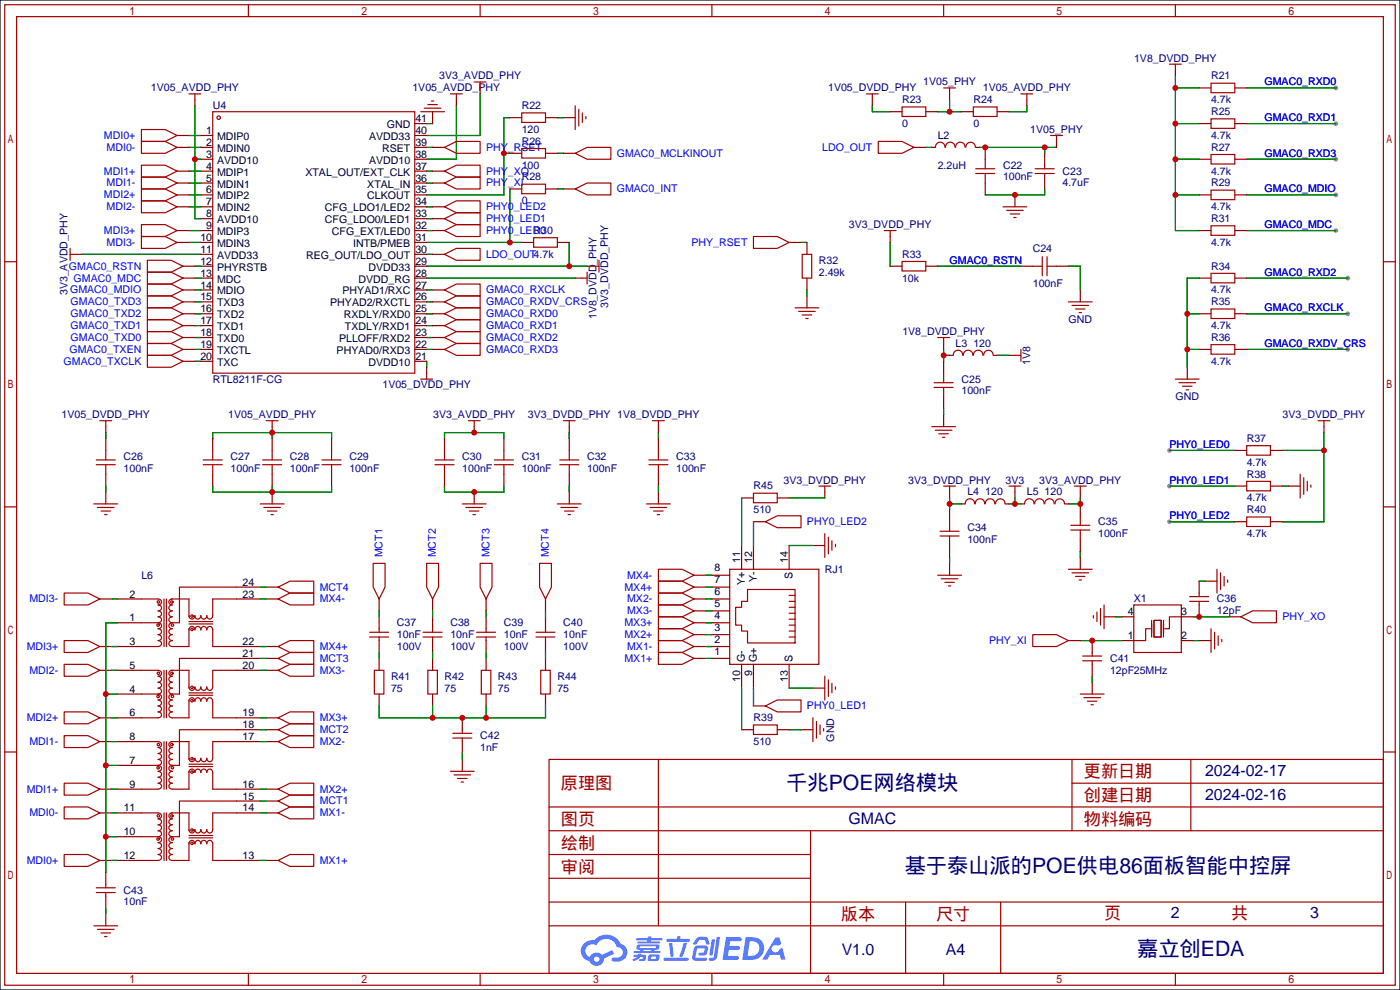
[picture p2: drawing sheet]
<svg xmlns="http://www.w3.org/2000/svg" width="299mm" height="212mm" viewBox="0 0 299 212" stroke-linecap="round" stroke-linejoin="round" font-family="sans-serif">
<defs><g id="words">
<g font-size="4.5" fill="#000080">
<text x="168" y="168.8">千兆POE网络模块</text>
<text x="193.4" y="186.6">基于泰山派的POE供电86面板智能中控屏</text>
<text x="243" y="204.4">嘉立创EDA</text>
</g>
<g font-size="3.7" fill="#a00000">
<text x="231.6" y="166.2">更新日期</text>
<text x="119.9" y="168.7">原理图</text>
<text x="231.6" y="171.2">创建日期</text>
<text x="119.9" y="176.3">图页</text>
<text x="231.6" y="176.3">物料编码</text>
<text x="119.9" y="181.4">绘制</text>
<text x="119.9" y="186.5">审阅</text>
<text x="179.7" y="196.6">版本</text>
<text x="200" y="196.6">尺寸</text>
<text x="236" y="196.4">页</text>
<text x="263.1" y="196.4">共</text>
</g>
<g font-size="3.4" fill="#000080">
<text x="257.6" y="165.9">2024-02-17</text>
<text x="257.6" y="171">2024-02-16</text>
<text x="181.3" y="176.1">GMAC</text>
<text x="250.3" y="196.2">2</text>
<text x="280" y="196.2">3</text>
<text x="179.9" y="204">V1.0</text>
<text x="202.1" y="204">A4</text>
</g>
<g font-size="2.3" fill="#000080">
<text x="93.9" y="17">3V3_AVDD_PHY</text>
<text x="242.4" y="13.2">1V8_DVDD_PHY</text>
<text x="258.8" y="17">R21</text>
<text x="32.3" y="19.5">1V05_AVDD_PHY</text>
<text x="45.5" y="23.3">U4</text>
<text x="88.1" y="19.5">1V05_AVDD_PHY</text>
<text x="111.5" y="23.3">R22</text>
<text x="177" y="19.5">1V05_DVDD_PHY</text>
<text x="192.8" y="22.1">R23</text>
<text x="197.3" y="18.3">1V05_PHY</text>
<text x="208" y="22.1">R24</text>
<text x="210.1" y="19.5">1V05_AVDD_PHY</text>
<text x="258.8" y="22.1">4.7k</text>
<text x="111.5" y="28.4">120</text>
<text x="192.8" y="27.1">0</text>
<text x="200.4" y="29.7">L2</text>
<text x="208" y="27.1">0</text>
<text x="220.2" y="28.4">1V05_PHY</text>
<text x="258.8" y="24.6">R25</text>
<text x="258.8" y="29.7">4.7k</text>
<text x="111.5" y="31">R26</text>
<text x="258.8" y="32.2">R27</text>
<text x="111.5" y="38.6">R28</text>
<text x="111.5" y="36">100</text>
<text x="200.4" y="36">2.2uH</text>
<text x="214.4" y="36">C22</text>
<text x="214.4" y="38.6">100nF</text>
<text x="227.1" y="37.3">C23</text>
<text x="227.1" y="39.8">4.7uF</text>
<text x="258.8" y="37.3">4.7k</text>
<text x="258.8" y="39.8">R29</text>
<text x="111.5" y="43.7">0</text>
<text x="258.8" y="44.9">4.7k</text>
<text x="258.8" y="47.5">R31</text>
<text x="114" y="50">R30</text>
<text x="181.4" y="48.7">3V3_DVDD_PHY</text>
<text x="220.7" y="53.8">C24</text>
<text x="258.8" y="52.5">4.7k</text>
<text x="175" y="56.4">R32</text>
<text x="175" y="58.9">2.49k</text>
<text x="192.8" y="55.1">R33</text>
<text x="258.8" y="57.6">R34</text>
<text x="14.4" y="63.1" transform="rotate(-90 14.4 63.1)">3V3_AVDD_PHY</text>
<text x="130" y="65.7" transform="rotate(-90 130 65.7)">3V3_DVDD_PHY</text>
<text x="192.8" y="60.2">10k</text>
<text x="220.7" y="61.4">100nF</text>
<text x="258.8" y="62.7">4.7k</text>
<text x="258.8" y="65.2">R35</text>
<text x="127.5" y="68.3" transform="rotate(-90 127.5 68.3)">1V8_DVDD_PHY</text>
<text x="192.9" y="71.6">1V8_DVDD_PHY</text>
<text x="228.4" y="69.1">GND</text>
<text x="258.8" y="70.3">4.7k</text>
<text x="204.2" y="74.1">L3</text>
<text x="208" y="74.1">120</text>
<text x="220.2" y="78" transform="rotate(-90 220.2 78)">1V8</text>
<text x="258.8" y="72.9">R36</text>
<text x="258.8" y="77.9">4.7k</text>
<text x="45.5" y="81.8">RTL8211F-CG</text>
<text x="81.7" y="83">1V05_DVDD_PHY</text>
<text x="205.5" y="81.8">C25</text>
<text x="13.2" y="89.4">1V05_DVDD_PHY</text>
<text x="48.8" y="89.4">1V05_AVDD_PHY</text>
<text x="92.6" y="89.4">3V3_AVDD_PHY</text>
<text x="112.8" y="89.4">3V3_DVDD_PHY 1V8_DVDD_PHY</text>
<text x="205.5" y="84.3">100nF</text>
<text x="251.2" y="85.6">GND</text>
<text x="274.1" y="89.4">3V3_DVDD_PHY</text>
<text x="266.4" y="94.5">R37</text>
<text x="26.4" y="98.3">C26</text>
<text x="26.4" y="100.8">100nF</text>
<text x="49.3" y="98.3">C27</text>
<text x="49.3" y="100.8">100nF</text>
<text x="62" y="98.3">C28</text>
<text x="62" y="100.8">100nF</text>
<text x="74.7" y="98.3">C29</text>
<text x="74.7" y="100.8">100nF</text>
<text x="98.8" y="98.3">C30</text>
<text x="98.8" y="100.8">100nF</text>
<text x="111.5" y="98.3">C31</text>
<text x="111.5" y="100.8">100nF</text>
<text x="125.5" y="98.3">C32</text>
<text x="125.5" y="100.8">100nF</text>
<text x="144.5" y="98.3">C33</text>
<text x="144.5" y="100.8">100nF</text>
<text x="266.4" y="99.5">4.7k</text>
<text x="161" y="104.6">R45</text>
<text x="167.5" y="103.3">3V3_DVDD_PHY</text>
<text x="194.1" y="103.3">3V3_DVDD_PHY</text>
<text x="206.8" y="105.9">L4</text>
<text x="210.6" y="105.9">120</text>
<text x="214.9" y="103.3">3V3</text>
<text x="219.5" y="105.9">L5</text>
<text x="222.1" y="103.3">3V3_AVDD_PHY</text>
<text x="223.3" y="105.9">120</text>
<text x="266.4" y="102.1">R38</text>
<text x="266.4" y="107.2">4.7k</text>
<text x="161" y="109.7">510</text>
<text x="206.8" y="113.5">C34</text>
<text x="234.7" y="112.2">C35</text>
<text x="266.4" y="109.7">R40</text>
<text x="206.8" y="116">100nF</text>
<text x="234.7" y="114.8">100nF</text>
<text x="266.4" y="114.8">4.7k</text>
<text x="30.2" y="123.7">L6</text>
<text x="176.3" y="122.4">RJ1</text>
<text x="242.3" y="128.7">X1</text>
<text x="260.1" y="128.7">C36</text>
<text x="260.1" y="131.3">12pF</text>
<text x="84.8" y="133.8">C37</text>
<text x="84.8" y="136.4">10nF</text>
<text x="96.3" y="133.8">C38</text>
<text x="96.3" y="136.4">10nF</text>
<text x="107.7" y="133.8">C39</text>
<text x="107.7" y="136.4">10nF</text>
<text x="120.4" y="133.8">C40</text>
<text x="120.4" y="136.4">10nF</text>
<text x="84.8" y="138.9">100V</text>
<text x="96.3" y="138.9">100V</text>
<text x="107.7" y="138.9">100V</text>
<text x="120.4" y="138.9">100V</text>
<text x="237.2" y="141.4">C41</text>
<text x="237.2" y="144">12pF25MHz</text>
<text x="83.6" y="145.3">R41</text>
<text x="83.6" y="147.8">75</text>
<text x="95" y="145.3">R42</text>
<text x="95" y="147.8">75</text>
<text x="106.4" y="145.3">R43</text>
<text x="106.4" y="147.8">75</text>
<text x="119.1" y="145.3">R44</text>
<text x="119.1" y="147.8">75</text>
<text x="161" y="154.1">R39</text>
<text x="102.6" y="158">C42</text>
<text x="102.6" y="160.5">1nF</text>
<text x="161" y="159.2">510</text>
<text x="178.3" y="158.5" transform="rotate(-90 178.3 158.5)">GND</text>
<text x="26.4" y="191">C43</text>
<text x="26.4" y="193.5">10nF</text>
</g>
<g font-size="2.3" fill="#00f">
<text x="270.3" y="18.3">GMAC0_RXD0</text>
<text x="22.2" y="29.7">MDI0+</text>
<text x="270.3" y="25.9">GMAC0_RXD1</text>
<text x="22.8" y="32.2">MDI0-</text>
<text x="103.9" y="32.2">PHY_RSET</text>
<text x="131.8" y="33.5">GMAC0_MCLKINOUT</text>
<text x="175.7" y="32.2">LDO_OUT</text>
<text x="270.3" y="33.5">GMAC0_RXD3</text>
<text x="22.2" y="37.3">MDI1+</text>
<text x="22.8" y="39.8">MDI1-</text>
<text x="103.9" y="39.8">PHY_XI</text>
<text x="103.9" y="37.3">PHY_XO</text>
<text x="131.8" y="41.1">GMAC0_INT</text>
<text x="270.3" y="41.1">GMAC0_MDIO</text>
<text x="22.2" y="42.4">MDI2+</text>
<text x="22.8" y="44.9">MDI2-</text>
<text x="103.9" y="47.5">PHY0_LED1</text>
<text x="103.9" y="44.9">PHY0_LED2</text>
<text x="22.2" y="50">MDI3+</text>
<text x="22.8" y="52.5">MDI3-</text>
<text x="103.9" y="50">PHY0_LED0</text>
<text x="147.8" y="52.5">PHY_RSET</text>
<text x="270.3" y="48.7">GMAC0_MDC</text>
<text x="14.7" y="57.6">GMAC0_RSTN</text>
<text x="103.9" y="55.1">LDO_OUT4.7k</text>
<text x="202.9" y="56.4">GMAC0_RSTN</text>
<text x="270.3" y="58.9">GMAC0_RXD2</text>
<text x="15" y="62.7">GMAC0_MDIO</text>
<text x="15.1" y="65.2">GMAC0_TXD3</text>
<text x="15.7" y="60.2">GMAC0_MDC</text>
<text x="103.9" y="65.2">GMAC0_RXDV_CRS</text>
<text x="103.9" y="62.7">GMAC0_RXCLK</text>
<text x="15.1" y="70.3">GMAC0_TXD1</text>
<text x="15.1" y="67.8">GMAC0_TXD2</text>
<text x="103.9" y="67.8">GMAC0_RXD0</text>
<text x="103.9" y="70.3">GMAC0_RXD1</text>
<text x="270.3" y="66.5">GMAC0_RXCLK</text>
<text x="13.6" y="77.9">GMAC0_TXCLK</text>
<text x="14.9" y="75.4">GMAC0_TXEN</text>
<text x="15.1" y="72.9">GMAC0_TXD0</text>
<text x="103.9" y="72.9">GMAC0_RXD2</text>
<text x="103.9" y="75.4">GMAC0_RXD3</text>
<text x="270.3" y="74.1">GMAC0_RXDV_CRS</text>
<text x="249.9" y="95.7">PHY0_LED0</text>
<text x="249.9" y="103.3">PHY0_LED1</text>
<text x="172.5" y="112.2">PHY0_LED2</text>
<text x="249.9" y="111">PHY0_LED2</text>
<text x="81.8" y="119.1" transform="rotate(-90 81.8 119.1)">MCT1</text>
<text x="93.2" y="119.1" transform="rotate(-90 93.2 119.1)">MCT2</text>
<text x="104.6" y="119.1" transform="rotate(-90 104.6 119.1)">MCT3</text>
<text x="117.3" y="119.1" transform="rotate(-90 117.3 119.1)">MCT4</text>
<text x="134" y="123.7">MX4-</text>
<text x="6.3" y="128.7">MDI3-</text>
<text x="68.3" y="126.2">MCT4</text>
<text x="68.3" y="128.7">MX4-</text>
<text x="133.5" y="126.2">MX4+</text>
<text x="134" y="128.7">MX2-</text>
<text x="134" y="131.3">MX3-</text>
<text x="133.5" y="136.4">MX2+</text>
<text x="133.5" y="133.8">MX3+</text>
<text x="211.4" y="137.6">PHY_XI</text>
<text x="274.1" y="132.6">PHY_XO</text>
<text x="5.7" y="138.9">MDI3+</text>
<text x="6.3" y="144">MDI2-</text>
<text x="68.3" y="141.4">MCT3</text>
<text x="68.3" y="138.9">MX4+</text>
<text x="68.3" y="144">MX3-</text>
<text x="133.5" y="141.4">MX1+</text>
<text x="134" y="138.9">MX1-</text>
<text x="5.7" y="154.1">MDI2+</text>
<text x="68.3" y="154.1">MX3+</text>
<text x="172.5" y="151.6">PHY0_LED1</text>
<text x="6.3" y="159.2">MDI1-</text>
<text x="68.3" y="156.7">MCT2</text>
<text x="68.3" y="159.2">MX2-</text>
<text x="5.7" y="169.4">MDI1+</text>
<text x="68.3" y="171.9">MCT1</text>
<text x="68.3" y="169.4">MX2+</text>
<text x="6.3" y="174.5">MDI0-</text>
<text x="68.3" y="174.5">MX1-</text>
<text x="5.7" y="184.6">MDI0+</text>
<text x="68.3" y="184.6">MX1+</text>
</g>
<g font-size="2.3">
<text x="44.1" y="28.6">1</text>
<text x="46.4" y="29.9">MDIP0</text>
<text x="78.9" y="29.9">AVDD33</text>
<text x="82.7" y="27.4">GND</text>
<text x="88.8" y="28.6">40</text>
<text x="88.8" y="26.1">41</text>
<text x="44.1" y="31.2">2</text>
<text x="44.1" y="33.7">3</text>
<text x="46.4" y="32.5">MDIN0</text>
<text x="46.4" y="35">AVDD10</text>
<text x="78.9" y="35">AVDD10</text>
<text x="81.7" y="32.5">RSET</text>
<text x="88.8" y="33.7">38</text>
<text x="88.8" y="31.2">39</text>
<text x="44.1" y="36.3">4</text>
<text x="44.1" y="38.8">5</text>
<text x="44.1" y="41.3">6</text>
<text x="46.4" y="37.5">MDIP1</text>
<text x="46.4" y="40.1">MDIN1</text>
<text x="65.3" y="37.5">XTAL_OUT/EXT_CLK</text>
<text x="78.5" y="40.1">XTAL_IN</text>
<text x="88.8" y="41.3">35</text>
<text x="88.8" y="38.8">36</text>
<text x="88.8" y="36.3">37</text>
<text x="44.1" y="43.9">7</text>
<text x="44.1" y="46.4">8</text>
<text x="46.4" y="42.6">MDIP2</text>
<text x="46.4" y="45.2">MDIN2</text>
<text x="46.4" y="47.7">AVDD10</text>
<text x="69.4" y="47.7">CFG_LDO0/LED1</text>
<text x="69.4" y="45.2">CFG_LDO1/LED2</text>
<text x="78.5" y="42.6">CLKOUT</text>
<text x="88.8" y="46.4">33</text>
<text x="88.8" y="43.9">34</text>
<text x="42.8" y="51.5">10</text>
<text x="44.1" y="49">9</text>
<text x="46.4" y="50.2">MDIP3</text>
<text x="46.4" y="52.8">MDIN3</text>
<text x="70.9" y="50.2">CFG_EXT/LED0</text>
<text x="75.5" y="52.8">INTB/PMEB</text>
<text x="88.8" y="51.5">31</text>
<text x="88.8" y="49">32</text>
<text x="42.8" y="54">11</text>
<text x="42.8" y="56.6">12</text>
<text x="42.8" y="59.1">13</text>
<text x="46.4" y="55.3">AVDD33</text>
<text x="46.4" y="57.9">PHYRSTB</text>
<text x="65.4" y="55.3">REG_OUT/LDO_OUT</text>
<text x="78.8" y="57.9">DVDD33</text>
<text x="88.8" y="59.1">28</text>
<text x="88.8" y="56.6">29</text>
<text x="88.8" y="54">30</text>
<text x="42.8" y="61.7">14</text>
<text x="42.8" y="64.2">15</text>
<text x="46.4" y="60.4">MDC</text>
<text x="46.4" y="62.9">MDIO</text>
<text x="46.4" y="65.5">TXD3</text>
<text x="70.6" y="65.5">PHYAD2/RXCTL</text>
<text x="73.2" y="62.9">PHYAD1/RXC</text>
<text x="76.6" y="60.4">DVDD_RG</text>
<text x="88.8" y="64.2">26</text>
<text x="88.8" y="61.7">27</text>
<text x="42.8" y="66.7">16</text>
<text x="42.8" y="69.3">17</text>
<text x="42.8" y="71.8">18</text>
<text x="46.4" y="68">TXD2</text>
<text x="46.4" y="70.6">TXD1</text>
<text x="73.5" y="68">RXDLY/RXD0</text>
<text x="73.7" y="70.6">TXDLY/RXD1</text>
<text x="88.8" y="71.8">23</text>
<text x="88.8" y="69.3">24</text>
<text x="88.8" y="66.7">25</text>
<text x="42.8" y="74.4">19</text>
<text x="42.8" y="76.9">20</text>
<text x="46.4" y="73.1">TXD0</text>
<text x="46.4" y="75.6">TXCTL</text>
<text x="72" y="75.6">PHYAD0/RXD3</text>
<text x="72.5" y="73.1">PLLOFF/RXD2</text>
<text x="88.8" y="76.9">21</text>
<text x="88.8" y="74.4">22</text>
<text x="46.4" y="78.2">TXC</text>
<text x="78.8" y="78.2">DVDD10</text>
<text x="51.8" y="125.2">24</text>
<text x="152.7" y="124.7">7</text>
<text x="152.7" y="122.1">8</text>
<text x="158.2" y="120.4" transform="rotate(-90 158.2 120.4)">11</text>
<text x="159.2" y="125" transform="rotate(-90 159.2 125)">Y+</text>
<text x="160.7" y="120.4" transform="rotate(-90 160.7 120.4)">12</text>
<text x="161.7" y="124.4" transform="rotate(-90 161.7 124.4)">Y-</text>
<text x="168.3" y="120.4" transform="rotate(-90 168.3 120.4)">14</text>
<text x="169.4" y="123.7" transform="rotate(-90 169.4 123.7)">S</text>
<text x="27.7" y="127.7">2</text>
<text x="51.8" y="127.7">23</text>
<text x="152.7" y="129.8">5</text>
<text x="152.7" y="127.2">6</text>
<text x="241.1" y="131.5">4</text>
<text x="252.5" y="131.5">3</text>
<text x="27.7" y="137.9">3</text>
<text x="27.7" y="132.8">1</text>
<text x="51.8" y="137.9">22</text>
<text x="152.7" y="137.4">2</text>
<text x="152.7" y="134.8">3</text>
<text x="152.7" y="132.3">4</text>
<text x="241.1" y="136.6">1</text>
<text x="252.5" y="136.6">2</text>
<text x="27.7" y="142.9">5</text>
<text x="51.8" y="140.4">21</text>
<text x="51.8" y="142.9">20</text>
<text x="152.7" y="139.9">1</text>
<text x="159.2" y="141.5" transform="rotate(-90 159.2 141.5)">G-</text>
<text x="161.7" y="141.5" transform="rotate(-90 161.7 141.5)">G+</text>
<text x="169.4" y="141.5" transform="rotate(-90 169.4 141.5)">S</text>
<text x="27.7" y="148">4</text>
<text x="158.2" y="145.8" transform="rotate(-90 158.2 145.8)">10</text>
<text x="160.7" y="144.5" transform="rotate(-90 160.7 144.5)">9</text>
<text x="168.3" y="145.8" transform="rotate(-90 168.3 145.8)">13</text>
<text x="27.7" y="153.1">6</text>
<text x="51.8" y="153.1">19</text>
<text x="51.8" y="155.6">18</text>
<text x="27.7" y="158.2">8</text>
<text x="51.8" y="158.2">17</text>
<text x="27.7" y="163.3">7</text>
<text x="26.4" y="173.4">11</text>
<text x="27.7" y="168.3">9</text>
<text x="51.8" y="168.3">16</text>
<text x="51.8" y="170.9">15</text>
<text x="51.8" y="173.4">14</text>
<text x="26.4" y="178.5">10</text>
<text x="26.4" y="183.6">12</text>
<text x="51.8" y="183.6">13</text>
</g>
</g></defs>
<path d="M0 0h299.2v211.6h-299.2z" fill="#fff" stroke="#000" stroke-width=".25"/>
<g fill="#999">
<circle cx="285.5" cy="18.8" r=".51"/>
<circle cx="285.5" cy="26.4" r=".51"/>
<circle cx="285.5" cy="34" r=".51"/>
<circle cx="288" cy="59.4" r=".51"/>
<circle cx="288" cy="67.1" r=".51"/>
<circle cx="288" cy="74.7" r=".51"/>
<circle cx="285.5" cy="41.7" r=".51"/>
<circle cx="285.5" cy="49.3" r=".51"/>
<circle cx="249.9" cy="96.3" r=".51"/>
<circle cx="249.9" cy="103.9" r=".51"/>
<circle cx="249.9" cy="111.5" r=".51"/>
</g>
<g fill="none" stroke="#a10000" stroke-width=".25">
<path d="M1 1h297.2v209.6h-297.2zM3.6 3.6h292.1v204.4h-292.1zM53.1 1v2.6M102.6 1v2.6M152.1 1v2.6M201.7 1v2.6M251.2 1v2.6M1 55.9h2.6M295.7 55.9h2.5M1 108.3h2.6M295.7 108.3h2.5M1 160.7h2.6"/>
<path d="M117.3 162.3h178.4v45.7h-178.4zM117.3 177.5h178.4M117.3 172.5h178.4M140.7 162.3v35.6M173.2 177.5v30.5M229.1 162.3v15.2M229.1 167.4h66.6M254.5 162.3v15.2M295.7 160.7h2.5M117.3 182.6h55.9M117.3 197.9h178.4M117.3 192.8h178.4"/>
<path d="M117.3 187.7h55.9M193.5 192.8v15.2M213.9 192.8v15.2M53.1 208v2.6M102.6 208v2.6M152.1 208v2.6M201.7 208v2.6M251.2 208v2.6"/>
</g>
<g fill="#5487ff">
<path d="M155.2 200.3h2.6a.48 .48 0 0 1 .7 .4 .48 .48 0 0 1-.6 .4h-1.8l-.2 1.1h1.9a.43 .43 0 0 1 .4 .4 .43 .43 0 0 1-.5 .4h-1.9l-.2 1.3h1.7a.45 .45 0 0 1 .5 .2 .45 .45 0 0 1-.1 .6h-3.3z"/>
<path d="M165.7 200.3h.9l.4 1.5-.8 .3a.84 .84 0 0 0-1.2 .3 .84 .84 0 0 0 .4 1.1 .84 .84 0 0 0 1.1-.4l.1-.2 .6-.3 .7 2.5h-1l-.2-1h-2.1l-.6 1h-1.1z"/>
<path d="M152.1 200.8h.7l-.5 3.1a.36 .36 0 0 1-.3 .3 .36 .36 0 0 1-.4-.3z"/>
<path d="M153.2 200.2h.7l-.6 4.3a1.13 1.13 0 0 1-1.8 .6l.2-.4h.7l.2-.2z"/>
<path d="M148.9 200.6l.6-.4h1a.77 .77 0 0 1 .9 .5l.3 1-.2 .2h-.5l-.3-.9-.2-.2-1 .1-.7 1-.6-.1-.1-.2z"/>
<path d="M148.4 202.4l.6-.3h1.7a.81 .81 0 0 1 .7 .5 .81 .81 0 0 1-.2 .8 .81 .81 0 0 1-.9 .8h-.7a.32 .32 0 0 1-.3-.3 .32 .32 0 0 1 .4-.3h.7l.2-.9-1.6 .1-.4 1.8 2.2 .1a.32 .32 0 0 1 .3 .4 .32 .32 0 0 1-.4 .2h-2.2l-.5-.3-.1-.5z"/>
<path d="M141.9 204.7h5a.33 .33 0 0 1 .3 .3 .33 .33 0 0 1-.3 .3h-4.9l-.2-.1z"/>
<path d="M146.1 201.5h.8l-.7 2a.98 .98 0 0 1-.7 1.1l-.3-.3z"/>
<path d="M143 201.6h.7l.3 2.5a.34 .34 0 0 1-.3 .4 .34 .34 0 0 1-.4-.3z"/>
<path d="M142.5 200.7h2.1l.3-.6h.6l-.1 .6h1.7a.32 .32 0 0 1 .4 .3 .32 .32 0 0 1-.4 .3h-4.5l-.2-.2z"/>
<path d="M135.5 204.1h.9l.1-.3h.6v.3h.8a.82 .82 0 0 1-.5 1.3h-.8v-.4l.7-.1 .1-.3a.68 .68 0 0 0-1 .4l-1.1 .4-.1-.4 .9-.5h-.7z"/>
<path d="M136 200.5h2.4l.1-.3h.7v.3h2.2l.2 .3-.2 .2h-2.3v.2h1.8l.2 .3-.2 .1h-4.5l-.1-.4h2l.1-.2h-2.3l-.1-.2z"/>
<path d="M159.4 200.3l-.8 4.9h1.7a2.5 2.5 0 0 0 3-2.5 2.5 2.5 0 0 0-3.1-2.4zM160.3 201.1a1.61 1.61 0 0 1 2 1.5 1.61 1.61 0 0 1-1.8 1.7h-.7z"/>
<path d="M136.2 202a.55 .55 0 0 0-.2 .8 .55 .55 0 0 0 .7 .2l.1 .3h-1.3v.3l5.4 .1 .3-.2-.2-.2h-1.2l.2-.3a.7 .7 0 0 0 .8-.3 .7 .7 0 0 0 0-.8l-4.2-.1zM136.8 202.3l3.3-.1 .1 .1-.2 .3h-3.2zM137.5 203h1.7l-.2 .3h-1.4z"/>
<path d="M138.6 204.2a1.05 1.05 0 0 0 0 1.2 2.91 2.91 0 0 0 2.2-.2 .98 .98 0 0 0 0-1.2h-1.6zM139.2 204.5l.9-.1 .1 .4-.2 .2-.8-.1z"/>
<path d="M124.9 201.6a2.23 2.23 0 0 0-.7 2.3 2.23 2.23 0 0 0 1.8 1.6 1.58 1.58 0 0 0 1.8 .9 1.58 1.58 0 0 0 1.3-1.5l2.2-1.1-.5-.7-2.1 1a1.65 1.65 0 0 0-2.7 .4 1.45 1.45 0 0 1-.8-1.9 1.45 1.45 0 0 1 2-.7l.3 .1a2.3 2.3 0 0 1 2.3-1.3 2.3 2.3 0 0 1 2 1.7 1.12 1.12 0 0 1 1.3 1 1.12 1.12 0 0 1-1.1 1.2h-.7a.45 .45 0 0 0-.6 .4 .45 .45 0 0 0 .5 .5 2.21 2.21 0 0 0 2.2-.5 2.21 2.21 0 0 0 .5-2.3 2.13 2.13 0 0 0-1.3-1.1 3.3 3.3 0 0 0-5.6-.7l-1.1 .1zM127 205a.57 .57 0 0 1 1.1 0 .57 .57 0 0 1-1.1 0z"/>
</g>
<g fill="none" stroke="#870000" stroke-width=".25">
<path d="M102.6 18.8v1.3M251.2 15v1.3M256.3 18.8h2.5M263.9 18.8h2.5M37.8 29h2.6M37.8 31.5h2.6M37.8 36.6h2.6M37.8 39.1h2.6M41.7 21.3v1.3M42.9 29h2.6M42.9 31.5h2.6M42.9 34h2.6"/>
<path d="M42.9 36.6h2.6M42.9 39.1h2.6M88.6 29h2.6M88.6 31.5h2.6M88.6 34h2.6M88.6 36.6h2.6M88.6 39.1h2.6M88.6 26.4h2.6M92.5 23.9v2.5M92.5 31.5h2.5M92.5 36.6h2.5M92.5 39.1h2.5"/>
<path d="M97.5 21.3v1.3M109 32.8h2.5M109 25.1h2.5M116.6 32.8h2.5M116.6 25.1h2.5M120.4 32.8h2.5M120.4 25.1h2.5M186.4 21.3v1.3M190.2 23.9h2.6M195.3 31.5h2.6M197.9 23.9h2.5M199.1 31.5h.8"/>
<path d="M202.9 20.1v1.2M205.5 23.9h2.5M208.5 31.5h.8M210.6 31.5v2.5M210.6 39.1v2.6M213.1 23.9h2.5M219.5 21.3v1.3M223.3 32.8v2.5M223.3 37.8v2.6M225.8 30.2v1.3M256.3 34h2.5M256.3 26.4h2.5"/>
<path d="M263.9 34h2.5M263.9 26.4h2.5M16.3 54.4h1.2M37.8 41.7h2.6M37.8 44.2h2.6M37.8 49.3h2.6M37.8 51.8h2.6M39.1 56.9h2.6M39.1 59.4h2.6M42.9 41.7h2.6M42.9 44.2h2.6M42.9 46.7h2.6"/>
<path d="M42.9 49.3h2.6M42.9 51.8h2.6M42.9 54.4h2.6M42.9 56.9h2.6M42.9 59.4h2.6M88.6 41.7h2.6M88.6 44.2h2.6M88.6 46.7h2.6M88.6 49.3h2.6M88.6 51.8h2.6M88.6 54.4h2.6M88.6 56.9h2.6"/>
<path d="M88.6 59.4h2.6M92.5 44.2h2.5M92.5 46.7h2.5M92.5 49.3h2.5M92.5 54.4h2.5M109 40.4h2.5M111.5 51.8h2.5M116.6 40.4h2.5M119.1 51.8h2.6M120.4 40.4h2.5M122.9 59.4h1.3M125.5 56.9h1.2"/>
<path d="M168.7 51.8h2.5M172.5 51.8v2.6M172.5 59.4v2.6M190.2 56.9h2.6M190.2 50.5v1.3M197.9 56.9h2.5M216.9 41.7v2.5M218.2 56.9h2.5M225.8 56.9h2.5M256.3 41.7h2.5M256.3 49.3h2.5M256.3 59.4h2.5"/>
<path d="M263.9 41.7h2.5M263.9 49.3h2.5M263.9 59.4h2.5M39.1 62h2.6M39.1 64.5h2.6M39.1 67.1h2.6M39.1 69.6h2.6M39.1 72.1h2.6M39.1 74.7h2.6M39.1 77.2h2.6M42.9 62h2.6M42.9 64.5h2.6"/>
<path d="M42.9 67.1h2.6M42.9 69.6h2.6M42.9 72.1h2.6M42.9 74.7h2.6M42.9 77.2h2.6M88.6 62h2.6M88.6 64.5h2.6M88.6 67.1h2.6M88.6 69.6h2.6M88.6 72.1h2.6M88.6 74.7h2.6M88.6 77.2h2.6"/>
<path d="M91.2 78.5v1.3M92.5 62h2.5M92.5 64.5h2.5M92.5 67.1h2.5M92.5 69.6h2.5M92.5 72.1h2.5M92.5 74.7h2.5M172.5 63.2v2.6M201.7 73.4v1.3M201.7 77.2v2.6M202.9 75.9h.8M212.3 75.9h.8"/>
<path d="M215.6 75.9h1.3M230.9 62v2.5M253.7 78.5v2.5M256.3 67.1h2.5M256.3 74.7h2.5M263.9 67.1h2.5M263.9 74.7h2.5M22.6 91.2v1.3M22.6 93.7v2.6M45.5 93.7v2.6M58.2 91.2v1.3M58.2 93.7v2.6"/>
<path d="M70.9 93.7v2.6M95 93.7v2.6M101.3 91.2v1.3M107.7 93.7v2.6M121.7 91.2v1.3M121.7 93.7v2.6M140.7 91.2v1.3M140.7 93.7v2.6M201.7 84.8v2.6M201.7 88.6v2.6M263.9 96.3h2.5M271.5 96.3h2.6"/>
<path d="M283 91.2v1.3M22.6 101.3v2.6M22.6 105.2v2.5M45.5 101.3v2.6M58.2 101.3v2.6M58.2 105.2v2.5M70.9 101.3v2.6M95 101.3v2.6M101.3 105.2v2.5M107.7 101.3v2.6M121.7 101.3v2.6M121.7 105.2v2.5"/>
<path d="M140.7 101.3v2.6M140.7 105.2v2.5M158.5 106.4h2.5M158.5 116.6v5.1M161 111.5h2.6M161 116.6v5.1M166.1 106.4h2.6M168.7 116.6v5.1M173.7 116.6h2.6M176.3 105.2v1.2M202.9 105.2v1.2M202.9 109v2.5"/>
<path d="M202.9 116.6v2.5M205.5 107.7h.7M214.9 107.7h.7M216.9 105.2v1.2M218.2 107.7h.7M227.6 107.7h.7M230.9 105.2v1.2M230.9 107.7v2.5M230.9 115.3v2.6M230.9 119.1v2.6M263.9 103.9h2.5M263.9 111.5h2.5"/>
<path d="M271.5 103.9h2.6M271.5 111.5h2.6M275.3 103.9h2.6M21.3 128h2.6M21.3 138.2h2.6M25.1 128h5.1M25.1 138.2h5.1M25.1 133.1h5.1M50.5 125.5h5.1M50.5 128h5.1M50.5 138.2h5.1M56.9 125.5h2.5"/>
<path d="M56.9 128h2.5M56.9 138.2h2.5M81 128v2.6M81 131.8v2.6M81 136.9v2.5M92.5 128v2.6M92.5 131.8v2.6M92.5 136.9v2.5M103.9 128v2.6M103.9 131.8v2.6M103.9 136.9v2.5M116.6 128v2.6"/>
<path d="M116.6 131.8v2.6M116.6 136.9v2.5M148.3 125.5h2.6M148.3 128h2.6M148.3 138.2h2.6M148.3 133.1h2.6M148.3 135.6h2.6M148.3 130.6h2.6M148.3 122.9h2.6M152.1 125.5h3.9M152.1 128h3.9M152.1 138.2h3.9"/>
<path d="M152.1 133.1h3.9M152.1 135.6h3.9M152.1 130.6h3.9M152.1 122.9h3.9M202.9 120.4v2.5M228.3 136.9h2.6M233.4 136.9v2.5M236 131.8h2.5M239.8 131.8h2.5M239.8 136.9h2.5M252.5 131.8h2.5M252.5 136.9h2.5"/>
<path d="M256.3 136.9h2.5M256.3 124.2v2.5M256.3 129.3v2.5M257.6 124.2h2.5M262.6 131.8h2.6M21.3 143.3h2.6M21.3 153.4h2.6M21.3 158.5h2.6M25.1 143.3h5.1M25.1 153.4h5.1M25.1 158.5h5.1M25.1 148.3h5.1"/>
<path d="M50.5 140.7h5.1M50.5 143.3h5.1M50.5 153.4h5.1M50.5 156h5.1M50.5 158.5h5.1M56.9 140.7h2.5M56.9 143.3h2.5M56.9 153.4h2.5M56.9 156h2.5M56.9 158.5h2.5M81 140.7v2.6M81 148.3v2.6"/>
<path d="M92.5 140.7v2.6M92.5 148.3v2.6M98.8 153.4v2.6M98.8 158.5v2.5M103.9 140.7v2.6M103.9 148.3v2.6M116.6 140.7v2.6M116.6 148.3v2.6M148.3 140.7h2.6M152.1 140.7h3.9M158.5 156h2.5M158.5 142v5.1"/>
<path d="M161 142v5.1M161 150.9h2.6M166.1 156h2.6M168.7 142v5.1M171.2 156h2.5M173.7 147.1h2.6M233.4 142v2.5M233.4 145.8v2.5M21.3 168.7h2.6M21.3 173.7h2.6M25.1 168.7h5.1M25.1 173.7h5.1"/>
<path d="M25.1 178.8h5.1M25.1 163.6h5.1M50.5 168.7h5.1M50.5 171.2h5.1M50.5 173.7h5.1M56.9 168.7h2.5M56.9 171.2h2.5M56.9 173.7h2.5M98.8 162.3v2.5M21.3 183.9h2.6M22.6 186.4v2.6M22.6 191.5v2.6"/>
<path d="M22.6 195.3v2.6M25.1 183.9h5.1M50.5 183.9h5.1M56.9 183.9h2.5"/>
</g>
<g fill="none" stroke="#a10000" stroke-width=".25">
<path d="M101.3 17.5h2.6M102.6 17.5v1.3M201.7 18.8h2.5M202.9 18.8v1.3M249.9 13.7h2.6M251.2 13.7v1.3M258.8 17.8h5.1v2h-5.1zM30.2 37.8h5.1l2.5 1.3-2.5 1.3h-5.1zM30.2 27.7h5.1l2.5 1.3-2.5 1.2h-5.1zM30.2 30.2h5.1l2.5 1.3-2.5 1.3h-5.1zM30.2 35.3h5.1l2.5 1.3-2.5 1.2h-5.1zM40.4 20.1h2.5"/>
<path d="M41.7 20.1v1.2M45.5 23.9h43.1v55.9h-43.1zM89.9 23.9h5.1M90.7 23.1h3.5M91.4 22.4h2.1M92.2 21.6h.5M95 39.1l2.5-1.3h5.1v2.6h-5.1zM95 36.6l2.5-1.3h5.1v2.5h-5.1zM95 31.5l2.5-1.3h5.1v2.6h-5.1zM96.3 20.1h2.5M97.5 20.1v1.2M111.5 39.4h5.1v2h-5.1z"/>
<path d="M111.5 31.8h5.1v2h-5.1zM111.5 24.1h5.1v2.1h-5.1zM122.9 32.8l2.6-1.3h5.1v2.5h-5.1zM122.9 22.6v5.1M123.7 23.4v3.5M124.5 24.1v2.1M125.2 24.9v.5M185.2 20.1h2.5M186.4 20.1v1.2M187.7 30.2h5.1l2.5 1.3-2.5 1.3h-5.1zM192.8 22.9h5.1v2h-5.1zM199.9 31.5a1.01 1.01 0 0 1 1-1.1 1.01 1.01 0 0 1 1.1 1.1"/>
<path d="M202.1 31.5a1.01 1.01 0 0 1 1-1.1 1.01 1.01 0 0 1 1 1.1M204.2 31.5a1.01 1.01 0 0 1 1-1.1 1.01 1.01 0 0 1 1.1 1.1M206.4 31.5a1.01 1.01 0 0 1 1-1.1 1.01 1.01 0 0 1 1 1.1M208 22.9h5.1v2h-5.1zM208.5 37.1h4.1M208.5 36.1h4.1M210.6 34v2.1M210.6 37.1v2M218.2 20.1h2.5M219.5 20.1v1.2M221.2 37.1h4.1M221.2 36.1h4.1"/>
<path d="M223.3 35.3v.8M223.3 37.1v.7M224.5 29h2.6M225.8 29v1.2M258.8 25.4h5.1v2h-5.1zM258.8 33h5.1v2.1h-5.1zM15 53.1v2.5M15 54.4h1.3M30.2 42.9h5.1l2.5 1.3-2.5 1.3h-5.1zM30.2 50.5h5.1l2.5 1.3-2.5 1.3h-5.1zM30.2 40.4h5.1l2.5 1.3-2.5 1.2h-5.1zM30.2 48h5.1l2.5 1.3-2.5 1.2h-5.1z"/>
<path d="M31.5 55.6h5.1l2.5 1.3-2.5 1.3h-5.1zM31.5 58.2h5.1l2.5 1.2-2.5 1.3h-5.1zM95 54.4l2.5-1.3h5.1v2.5h-5.1zM95 49.3l2.5-1.3h5.1v2.5h-5.1zM95 46.7l2.5-1.2h5.1v2.5h-5.1zM95 44.2l2.5-1.3h5.1v2.6h-5.1zM114 50.8h5.1v2h-5.1zM122.9 40.4l2.6-1.3h5.1v2.6h-5.1zM124.2 59.4h1.3M125.5 58.2v2.5M126.7 56.9h1.3M128 55.6v2.6"/>
<path d="M161 50.5h5.1l2.6 1.3-2.6 1.3h-5.1zM171.4 54.4h2.1v5h-2.1zM189 49.3h2.5M190.2 49.3v1.2M192.8 55.9h5.1v2h-5.1zM214.4 44.2h5.1M215.1 45h3.6M215.9 45.7h2M216.7 46.5h.5M220.7 56.9h2.1M222.8 54.9v4M223.8 56.9h2"/>
<path d="M223.8 54.9v4M258.8 40.6h5.1v2.1h-5.1zM258.8 48.3h5.1v2h-5.1zM258.8 58.4h5.1v2.1h-5.1zM31.5 60.7h5.1l2.5 1.3-2.5 1.2h-5.1zM31.5 75.9h5.1l2.5 1.3-2.5 1.3h-5.1zM31.5 73.4h5.1l2.5 1.3-2.5 1.2h-5.1zM31.5 70.9h5.1l2.5 1.2-2.5 1.3h-5.1zM31.5 68.3h5.1l2.5 1.3-2.5 1.3h-5.1zM31.5 65.8h5.1l2.5 1.3-2.5 1.2h-5.1zM31.5 63.2h5.1l2.5 1.3-2.5 1.3h-5.1zM91.2 79.8v1.2"/>
<path d="M95 64.5l2.5-1.3h5.1v2.6h-5.1zM95 62l2.5-1.3h5.1v2.5h-5.1zM95 67.1l2.5-1.3h5.1v2.5h-5.1zM95 69.6l2.5-1.3h5.1v2.6h-5.1zM95 72.1l2.5-1.2h5.1v2.5h-5.1zM95 74.7l2.5-1.3h5.1v2.5h-5.1zM169.9 65.8h5.1M170.7 66.5h3.5M171.4 67.3h2.1M172.2 68.1h.5M200.4 72.1h2.5M201.7 72.1v1.3"/>
<path d="M201.7 79.8v2M203.7 75.9a1.01 1.01 0 0 1 1.1-1.1 1.01 1.01 0 0 1 1 1.1M205.9 75.9a1.01 1.01 0 0 1 1-1.1 1.01 1.01 0 0 1 1 1.1M208 75.9a1.01 1.01 0 0 1 1.1-1.1 1.01 1.01 0 0 1 1 1.1M210.2 75.9a1.01 1.01 0 0 1 1-1 1.01 1.01 0 0 1 1.1 1M216.9 75.9h1.3M218.2 74.7v2.5M228.3 64.5h5.1M229.1 65.3h3.6M229.9 66h2M230.6 66.8h.5M258.8 66h5.1v2.1h-5.1z"/>
<path d="M258.8 73.7h5.1v2h-5.1zM20.6 99.3h4M20.6 98.3h4M21.3 89.9h2.6M22.6 89.9v1.3M22.6 96.3v2M22.6 99.3v2M43.4 99.3h4.1M43.4 98.3h4.1M45.5 96.3v2M45.5 99.3v2M56.1 99.3h4.1"/>
<path d="M56.1 98.3h4.1M56.9 89.9h2.5M58.2 89.9v1.3M58.2 96.3v2M58.2 99.3v2M68.8 99.3h4.1M68.8 98.3h4.1M70.9 96.3v2M70.9 99.3v2M89.9 81h2.6M93 99.3h4M93 98.3h4"/>
<path d="M95 96.3v2M95 99.3v2M100.1 89.9h2.5M101.3 89.9v1.3M105.7 99.3h4M105.7 98.3h4M107.7 96.3v2M107.7 99.3v2M119.6 99.3h4.1M119.6 98.3h4.1M120.4 89.9h2.5M121.7 89.9v1.3"/>
<path d="M121.7 96.3v2M121.7 99.3v2M138.7 99.3h4M138.7 98.3h4M139.4 89.9h2.6M140.7 89.9v1.3M140.7 96.3v2M140.7 99.3v2M199.1 91.2h5.1M199.6 81.8h4.1M199.6 82.8h4.1M199.9 91.9h3.6"/>
<path d="M200.7 92.7h2M201.4 93.5h.5M201.7 82.8v2M251.2 81h5.1M252 81.8h3.5M252.7 82.5h2.1M253.5 83.3h.5M266.4 95.2h5.1v2.1h-5.1zM281.7 89.9h2.5M283 89.9v1.3M20.1 107.7h5M20.8 108.5h3.6"/>
<path d="M21.6 109.2h2M22.4 110h.5M55.6 107.7h5.1M56.4 108.5h3.5M57.1 109.2h2.1M57.9 110h.5M98.8 107.7h5.1M99.6 108.5h3.5M100.3 109.2h2.1M101.1 110h.5M119.1 107.7h5.1M119.9 108.5h3.5"/>
<path d="M120.6 109.2h2.1M121.4 110h.5M138.2 107.7h5.1M138.9 108.5h3.6M139.7 109.2h2M140.5 110h.5M161 105.4h5.1v2h-5.1zM163.6 111.5l2.5-1.3h5.1v2.6h-5.1zM175 103.9h2.5M176.3 103.9v1.3M176.3 114v5.1M177 114.8v3.6"/>
<path d="M177.8 115.6v2M178.6 116.3v.5M200.9 114.6h4.1M200.9 113.5h4.1M201.7 103.9h2.5M202.9 103.9v1.3M202.9 111.5v2M202.9 114.6v2M206.3 107.7a1.01 1.01 0 0 1 1-1.1 1.01 1.01 0 0 1 1 1.1M208.4 107.7a1.01 1.01 0 0 1 1-1.1 1.01 1.01 0 0 1 1.1 1.1M210.6 107.7a1.01 1.01 0 0 1 1-1.1 1.01 1.01 0 0 1 1 1.1M212.8 107.7a1.01 1.01 0 0 1 1-1.1 1.01 1.01 0 0 1 1 1.1"/>
<path d="M215.6 103.9h2.6M216.9 103.9v1.3M219 107.7a1.01 1.01 0 0 1 1-1.1 1.01 1.01 0 0 1 1 1.1M221.1 107.7a1.01 1.01 0 0 1 1-1.1 1.01 1.01 0 0 1 1.1 1.1M223.3 107.7a1.01 1.01 0 0 1 1-1.1 1.01 1.01 0 0 1 1 1.1M225.5 107.7a1.01 1.01 0 0 1 1-1.1 1.01 1.01 0 0 1 1 1.1M228.9 113.3h4M228.9 112.3h4M229.6 103.9h2.6M230.9 103.9v1.3M230.9 110.2v2.1M230.9 113.3v2"/>
<path d="M266.4 102.9h5.1v2h-5.1zM266.4 110.5h5.1v2h-5.1zM277.9 101.3v5.1M278.6 102.1v3.6M279.4 102.9v2M280.2 103.6v.5M13.7 136.9h5.1l2.5 1.3-2.5 1.2h-5.1zM13.7 126.7h5.1l2.5 1.3-2.5 1.3h-5.1zM30.2 128h3.6a.64 .64 0 0 1 .7 .7 .64 .64 0 0 1-.7 .6 .64 .64 0 0 1 .7 .6 .64 .64 0 0 1-.7 .7 .64 .64 0 0 1 .7 .6 .64 .64 0 0 1-.7 .6 .64 .64 0 0 1 .7 .7 .64 .64 0 0 1-.7 .6 .64 .64 0 0 1 .7 .6 .64 .64 0 0 1-.7 .7 .64 .64 0 0 1 .7 .6 .64 .64 0 0 1-.7 .6 .64 .64 0 0 1 .7 .7 .64 .64 0 0 1-.7 .6 .64 .64 0 0 1 .7 .6 .64 .64 0 0 1-.7 .7h-3.6M30.2 133.1h3.8M35.1 128v10.2M35.6 128v10.2"/>
<path d="M36.6 128h3.8v3.8M36.8 133.1a.64 .64 0 0 0-.7 .6 .64 .64 0 0 0 .7 .7 .64 .64 0 0 0-.7 .6 .64 .64 0 0 0 .7 .6 .64 .64 0 0 0-.7 .7 .64 .64 0 0 0 .7 .6 .64 .64 0 0 0-.7 .6 .64 .64 0 0 0 .7 .7h3.6v-3.8M36.8 128a.64 .64 0 0 0-.7 .7 .64 .64 0 0 0 .7 .6 .64 .64 0 0 0-.7 .6 .64 .64 0 0 0 .7 .7 .64 .64 0 0 0-.7 .6 .64 .64 0 0 0 .7 .6 .64 .64 0 0 0-.7 .7 .64 .64 0 0 0 .7 .6M40.4 134.6a.64 .64 0 0 1 .3-.6 .64 .64 0 0 1 .7 0l.3 .6a.64 .64 0 0 1 .2-.6 .64 .64 0 0 1 .8 0l.2 .6a.64 .64 0 0 1 .3-.6 .64 .64 0 0 1 .7 0l.3 .6a.64 .64 0 0 1 .3-.6 .64 .64 0 0 1 .7 0l.3 .6v3.6h5M40.4 132.8h5.1M40.4 133.4h5.1M50.5 125.5h-12.1v7.6h-1.6M50.5 128h-5v3.6a.64 .64 0 0 1-.3 .6 .64 .64 0 0 1-.7 0l-.3-.6a.64 .64 0 0 1-.3 .6 .64 .64 0 0 1-.7 0l-.3-.6a.64 .64 0 0 1-.3 .6 .64 .64 0 0 1-.7 0l-.2-.6a.64 .64 0 0 1-.3 .6 .64 .64 0 0 1-.7 0l-.3-.6M59.4 125.5l2.6-1.3h5.1v2.5h-5.1zM59.4 138.2l2.6-1.3h5.1v2.5h-5.1zM59.4 128l2.6-1.3h5.1v2.6h-5.1zM79 136.1h4.1"/>
<path d="M79 135.1h4.1M79.8 120.4h2.5v5.1l-1.3 2.5-1.2-2.5zM81 134.4v.7M81 136.1v.8M90.4 136.1h4.1M90.4 135.1h4.1M91.2 120.4h2.5v5.1l-1.2 2.5-1.3-2.5zM92.5 134.4v.7M92.5 136.1v.8M101.9 136.1h4M101.9 135.1h4M102.6 120.4h2.6v5.1l-1.3 2.5-1.3-2.5z"/>
<path d="M103.9 134.4v.7M103.9 136.1v.8M114.6 136.1h4M114.6 135.1h4M115.3 120.4h2.6v5.1l-1.3 2.5-1.3-2.5zM116.6 134.4v.7M116.6 136.1v.8M140.7 139.4h5.1l2.5 1.3-2.5 1.3h-5.1zM140.7 134.4h5.1l2.5 1.2-2.5 1.3h-5.1zM140.7 131.8h5.1l2.5 1.3-2.5 1.3h-5.1zM140.7 124.2h5.1l2.5 1.3-2.5 1.2h-5.1zM140.7 136.9h5.1l2.5 1.3-2.5 1.2h-5.1z"/>
<path d="M140.7 126.7h5.1l2.5 1.3-2.5 1.3h-5.1zM140.7 129.3h5.1l2.5 1.3-2.5 1.2h-5.1zM140.7 121.7h5.1l2.5 1.2-2.5 1.3h-5.1zM156 121.7h19v20.3h-19zM159.8 126h10.1v11.4h-10.1v-2.5h-1.3v-1.3h-1.3v-3.8h1.3v-1.3h1.3zM168.7 136.1h1.2M168.7 128.5h1.2M168.7 134.9h1.2M168.7 133.6h1.2M168.7 132.3h1.2M168.7 131.1h1.2M168.7 129.8h1.2"/>
<path d="M168.7 127.3h1.2M200.4 122.9h5.1M201.2 123.7h3.5M201.9 124.5h2.1M202.7 125.2h.5M220.7 135.6h5.1l2.5 1.3-2.5 1.3h-5.1zM228.3 121.7h5.1M229.1 122.4h3.6M229.9 123.2h2M230.6 124h.5M233.4 139.4v.8M233.7 131.6v.5"/>
<path d="M234.4 130.8v2M235.2 130v3.6M236 129.3v5.1M242.3 129.3h10.2v10.1h-10.2zM245.9 134.4h-1v2.5h-2.6M246.1 132.6v3.5M246.6 132.6h1.6v3.5h-1.6zM248.7 132.6v3.5M252.5 131.8h-2.6v2.6h-1M254.3 128.5h4M254.3 127.5h4M256.3 126.7v.8"/>
<path d="M256.3 128.5v.8M258.8 134.4v5M259.6 135.1v3.6M260.1 121.7v5M260.3 135.9v2M260.9 122.4v3.6M261.1 136.7v.5M261.6 123.2v2M262.4 124v.5M265.2 131.8l2.5-1.2h5.1v2.5h-5.1zM13.7 152.1h5.1l2.5 1.3-2.5 1.3h-5.1zM13.7 157.2h5.1l2.5 1.3-2.5 1.3h-5.1z"/>
<path d="M13.7 142h5.1l2.5 1.3-2.5 1.2h-5.1zM30.2 158.5h3.6a.64 .64 0 0 1 .7 .6 .64 .64 0 0 1-.7 .7 .64 .64 0 0 1 .7 .6 .64 .64 0 0 1-.7 .6 .64 .64 0 0 1 .7 .7 .64 .64 0 0 1-.7 .6 .64 .64 0 0 1 .7 .6 .64 .64 0 0 1-.7 .7 .64 .64 0 0 1 .7 .6 .64 .64 0 0 1-.7 .6 .64 .64 0 0 1 .7 .7 .64 .64 0 0 1-.7 .6 .64 .64 0 0 1 .7 .7 .64 .64 0 0 1-.7 .6 .64 .64 0 0 1 .7 .6 .64 .64 0 0 1-.7 .7h-3.6M30.2 143.3h3.6a.64 .64 0 0 1 .7 .6 .64 .64 0 0 1-.7 .6 .64 .64 0 0 1 .7 .7 .64 .64 0 0 1-.7 .6 .64 .64 0 0 1 .7 .6 .64 .64 0 0 1-.7 .7 .64 .64 0 0 1 .7 .6 .64 .64 0 0 1-.7 .6 .64 .64 0 0 1 .7 .7 .64 .64 0 0 1-.7 .6 .64 .64 0 0 1 .7 .6 .64 .64 0 0 1-.7 .7 .64 .64 0 0 1 .7 .6 .64 .64 0 0 1-.7 .6 .64 .64 0 0 1 .7 .7 .64 .64 0 0 1-.7 .6h-3.6M30.2 148.3h3.8M35.1 143.3v10.1M35.1 158.5v10.2M35.6 143.3v10.1M35.6 158.5v10.2M36.6 143.3h3.8v3.8M36.6 158.5h3.8v3.8M36.8 158.5a.64 .64 0 0 0-.7 .6 .64 .64 0 0 0 .7 .7 .64 .64 0 0 0-.7 .6 .64 .64 0 0 0 .7 .6 .64 .64 0 0 0-.7 .7 .64 .64 0 0 0 .7 .6 .64 .64 0 0 0-.7 .6 .64 .64 0 0 0 .7 .7M36.8 143.3a.64 .64 0 0 0-.7 .6 .64 .64 0 0 0 .7 .6 .64 .64 0 0 0-.7 .7 .64 .64 0 0 0 .7 .6 .64 .64 0 0 0-.7 .6 .64 .64 0 0 0 .7 .7 .64 .64 0 0 0-.7 .6 .64 .64 0 0 0 .7 .6"/>
<path d="M36.8 148.3a.64 .64 0 0 0-.7 .7 .64 .64 0 0 0 .7 .6 .64 .64 0 0 0-.7 .6 .64 .64 0 0 0 .7 .7 .64 .64 0 0 0-.7 .6 .64 .64 0 0 0 .7 .6 .64 .64 0 0 0-.7 .7 .64 .64 0 0 0 .7 .6h3.6v-3.8M40.4 149.9a.64 .64 0 0 1 .3-.7 .64 .64 0 0 1 .7 0l.3 .7a.64 .64 0 0 1 .2-.7 .64 .64 0 0 1 .8 0l.2 .7a.64 .64 0 0 1 .3-.7 .64 .64 0 0 1 .7 0l.3 .7a.64 .64 0 0 1 .3-.7 .64 .64 0 0 1 .7 0l.3 .7v3.5h5M40.4 148.6h5.1M40.4 148.1h5.1M50.5 158.5h-5v3.6a.64 .64 0 0 1-.3 .6 .64 .64 0 0 1-.7 0l-.3-.6a.64 .64 0 0 1-.3 .6 .64 .64 0 0 1-.7 0l-.3-.6a.64 .64 0 0 1-.3 .6 .64 .64 0 0 1-.7 0l-.2-.6a.64 .64 0 0 1-.3 .6 .64 .64 0 0 1-.7 0l-.3-.6M50.5 156h-12.1v7.6h-1.6M50.5 143.3h-5v3.5a.64 .64 0 0 1-.3 .7 .64 .64 0 0 1-.7-.1l-.3-.6a.64 .64 0 0 1-.3 .7 .64 .64 0 0 1-.7-.1l-.3-.6a.64 .64 0 0 1-.3 .7 .64 .64 0 0 1-.7-.1l-.2-.6a.64 .64 0 0 1-.3 .7 .64 .64 0 0 1-.7-.1l-.3-.6M50.5 140.7h-12.1v7.6h-1.6M59.4 156l2.6-1.3h5.1v2.5h-5.1zM59.4 140.7l2.6-1.3h5.1v2.6h-5.1zM59.4 153.4l2.6-1.3h5.1v2.6h-5.1zM59.4 158.5l2.6-1.3h5.1v2.6h-5.1z"/>
<path d="M59.4 143.3l2.6-1.3h5.1v2.5h-5.1zM80 143.3h2v5h-2zM91.4 143.3h2.1v5h-2.1zM96.8 157.7h4M96.8 156.7h4M98.8 156v.7M98.8 157.7v.8M102.9 143.3h2v5h-2zM115.6 143.3h2v5h-2zM161 154.9h5.1v2.1h-5.1zM163.6 150.9l2.5-1.3h5.1v2.5h-5.1zM173.7 153.4v5.1"/>
<path d="M174.5 154.2v3.5M175.3 154.9v2.1M176 155.7v.5M176.3 144.5v5.1M177 145.3v3.5M177.8 146.1v2M178.6 146.8v.5M230.9 148.3h5.1M231.4 141.2h4.1M231.4 140.2h4.1M231.6 149.1h3.6M232.4 149.9h2"/>
<path d="M233.2 150.6h.5M233.4 141.2v.8M13.7 167.4h5.1l2.5 1.3-2.5 1.2h-5.1zM13.7 172.5h5.1l2.5 1.2-2.5 1.3h-5.1zM30.2 173.7h3.6a.64 .64 0 0 1 .7 .7 .64 .64 0 0 1-.7 .6 .64 .64 0 0 1 .7 .6 .64 .64 0 0 1-.7 .7 .64 .64 0 0 1 .7 .6 .64 .64 0 0 1-.7 .6 .64 .64 0 0 1 .7 .7 .64 .64 0 0 1-.7 .6 .64 .64 0 0 1 .7 .7 .64 .64 0 0 1-.7 .6 .64 .64 0 0 1 .7 .6 .64 .64 0 0 1-.7 .7 .64 .64 0 0 1 .7 .6 .64 .64 0 0 1-.7 .6 .64 .64 0 0 1 .7 .7 .64 .64 0 0 1-.7 .6h-3.6M30.2 178.8h3.8M30.2 163.6h3.8M35.1 173.7v10.2M35.6 173.7v10.2M36.6 173.7h3.8v3.8M36.8 173.7a.64 .64 0 0 0-.7 .7 .64 .64 0 0 0 .7 .6 .64 .64 0 0 0-.7 .6 .64 .64 0 0 0 .7 .7 .64 .64 0 0 0-.7 .6 .64 .64 0 0 0 .7 .6 .64 .64 0 0 0-.7 .7 .64 .64 0 0 0 .7 .6M36.8 178.8a.64 .64 0 0 0-.7 .7 .64 .64 0 0 0 .7 .6 .64 .64 0 0 0-.7 .6 .64 .64 0 0 0 .7 .7 .64 .64 0 0 0-.7 .6 .64 .64 0 0 0 .7 .6 .64 .64 0 0 0-.7 .7 .64 .64 0 0 0 .7 .6h3.6v-3.8"/>
<path d="M36.8 163.6a.64 .64 0 0 0-.7 .6 .64 .64 0 0 0 .7 .6 .64 .64 0 0 0-.7 .7 .64 .64 0 0 0 .7 .6 .64 .64 0 0 0-.7 .7 .64 .64 0 0 0 .7 .6 .64 .64 0 0 0-.7 .6 .64 .64 0 0 0 .7 .7h3.6v-3.9M40.4 165.1a.64 .64 0 0 1 .3-.6 .64 .64 0 0 1 .7 0l.3 .6a.64 .64 0 0 1 .2-.6 .64 .64 0 0 1 .8 0l.2 .6a.64 .64 0 0 1 .3-.6 .64 .64 0 0 1 .7 0l.3 .6a.64 .64 0 0 1 .3-.6 .64 .64 0 0 1 .7 0l.3 .6v3.6h5M40.4 179.1h5.1M40.4 178.6h5.1M40.4 163.8h5.1M40.4 163.3h5.1M50.5 173.7h-5v3.6a.64 .64 0 0 1-.3 .6 .64 .64 0 0 1-.7 0l-.3-.6a.64 .64 0 0 1-.3 .6 .64 .64 0 0 1-.7 0l-.3-.6a.64 .64 0 0 1-.3 .6 .64 .64 0 0 1-.7 0l-.2-.6a.64 .64 0 0 1-.3 .6 .64 .64 0 0 1-.7 0l-.3-.6M50.5 171.2h-12.1v7.6h-1.6M59.4 171.2l2.6-1.3h5.1v2.6h-5.1zM59.4 168.7l2.6-1.3h5.1v2.5h-5.1zM59.4 173.7l2.6-1.2h5.1v2.5h-5.1zM96.3 164.8h5"/>
<path d="M97 165.6h3.6M97.8 166.4h2M98.6 167.1h.5M13.7 182.6h5.1l2.5 1.3-2.5 1.3h-5.1zM20.1 197.9h5M20.6 190.8h4M20.6 189.7h4M20.8 198.6h3.6M21.6 199.4h2M22.6 189v.7M22.6 190.8v.7M40.4 180.3a.64 .64 0 0 1 .3-.6 .64 .64 0 0 1 .7 0l.3 .6a.64 .64 0 0 1 .2-.6 .64 .64 0 0 1 .8 0l.2 .6a.64 .64 0 0 1 .3-.6 .64 .64 0 0 1 .7 0l.3 .6a.64 .64 0 0 1 .3-.6 .64 .64 0 0 1 .7 0l.3 .6v3.6h5"/>
<path d="M59.4 183.9l2.6-1.3h5.1v2.6h-5.1zM22.4 200.2h.5"/>
<circle cx="46.7" cy="25.1" r=".38"/>
<circle cx="33.8" cy="133.6" r=".26"/>
<circle cx="33.8" cy="128.6" r=".26"/>
<circle cx="36.7" cy="128.7" r=".26"/>
<circle cx="36.8" cy="133.6" r=".26"/>
<circle cx="41" cy="134.5" r=".26"/>
<circle cx="41" cy="131.7" r=".26"/>
<circle cx="33.8" cy="148.8" r=".26"/>
<circle cx="33.8" cy="143.9" r=".26"/>
<circle cx="33.8" cy="159.1" r=".26"/>
<circle cx="36.7" cy="143.9" r=".26"/>
<circle cx="36.7" cy="159.1" r=".26"/>
<circle cx="36.8" cy="148.8" r=".26"/>
<circle cx="41" cy="149.8" r=".26"/>
<circle cx="41" cy="146.9" r=".26"/>
<circle cx="33.8" cy="164.1" r=".26"/>
<circle cx="33.8" cy="179.3" r=".26"/>
<circle cx="33.8" cy="174.4" r=".26"/>
<circle cx="36.7" cy="174.4" r=".26"/>
<circle cx="36.8" cy="164.1" r=".26"/>
<circle cx="36.8" cy="179.3" r=".26"/>
<circle cx="41" cy="177.4" r=".26"/>
<circle cx="41" cy="165" r=".26"/>
<circle cx="41" cy="162.2" r=".26"/>
<circle cx="41" cy="180.2" r=".26"/>
</g>
<g fill="none" stroke="#008700" stroke-width=".25">
<path d="M251.2 16.3v33h5.1M251.2 18.8h5.1M266.4 18.8h19.1M40.4 39.1h2.5M40.4 31.5h2.5M40.4 36.6h2.5M40.4 29h2.5M41.7 34h1.2M41.7 22.6v24.1h1.2M91.2 26.4h1.3M91.2 39.1h1.3M91.2 31.5h1.3"/>
<path d="M91.2 36.6h1.3M97.5 22.6v11.4h-6.3M102.6 20.1v8.9h-11.4M107.7 32.8h1.3M109 25.1h-1.3v16.6h-16.5M119.1 32.8h1.3M119.1 25.1h1.3M186.4 22.6v1.3h3.8M197.9 31.5h1.2M200.4 23.9h5.1M202.9 21.3v2.6M209.3 31.5h16.5"/>
<path d="M219.5 22.6v1.3h-3.9M223.3 31.5v1.3M251.2 26.4h5.1M251.2 34h5.1M266.4 26.4h19.1M266.4 34h19.1M17.5 54.4h25.4M40.4 49.3h2.5M40.4 51.8h2.5M40.4 44.2h2.5M40.4 41.7h2.5M41.7 56.9h1.2"/>
<path d="M41.7 59.4h1.2M91.2 49.3h1.3M91.2 51.8h20.3M91.2 44.2h1.3M91.2 46.7h1.3M91.2 54.4h1.3M91.2 56.9h34.3M91.2 59.4h31.7M109 40.4v11.4M119.1 40.4h1.3M121.7 51.8v5.1M171.2 51.8h1.3"/>
<path d="M190.2 51.8v5.1M200.4 56.9h17.8M223.3 40.4v1.3h-12.7M228.3 56.9h2.6v5.1M251.2 41.7h5.1M256.3 59.4h-2.6v19.1M266.4 49.3h19.1M266.4 41.7h19.1M266.4 59.4h21.6M41.7 62h1.2M41.7 77.2h1.2M41.7 74.7h1.2"/>
<path d="M41.7 72.1h1.2M41.7 69.6h1.2M41.7 67.1h1.2M41.7 64.5h1.2M91.2 62h1.3M91.2 74.7h1.3M91.2 72.1h1.3M91.2 69.6h1.3M91.2 67.1h1.3M91.2 64.5h1.3M91.2 77.2v1.3M172.5 62v1.2"/>
<path d="M201.7 74.7v2.5M201.7 75.9h1.2M213.1 75.9h2.5M253.7 74.7h2.6M253.7 67.1h2.6M266.4 74.7h21.6M266.4 67.1h21.6M22.6 92.5v1.2M45.5 93.7v-1.2h25.4v1.2M58.2 92.5v1.2M95 93.7v-1.2h12.7v1.2M121.7 92.5v1.2"/>
<path d="M140.7 92.5v1.2M201.7 87.4v1.2M249.9 96.3h14M274.1 96.3h8.9M283 92.5v19h-8.9M22.6 103.9v1.3M45.5 103.9v1.3h25.4v-1.3M58.2 103.9v1.3M95 103.9v1.3h12.7v-1.3M121.7 103.9v1.3M140.7 103.9v1.3M158.5 106.4v10.2"/>
<path d="M161 111.5v5.1M168.7 106.4h7.6M168.7 116.6h5M202.9 106.4v2.6M202.9 119.1v1.3M202.9 107.7h2.6M215.6 107.7h2.6M216.9 106.4v1.3M230.9 106.4v1.3h-2.6M230.9 117.9v1.2M249.9 103.9h14M249.9 111.5h14"/>
<path d="M274.1 103.9h1.2M23.9 138.2h1.2M23.9 128h1.2M25.1 133.1h-2.5v53.3M55.6 138.2h1.3M55.6 128h1.3M55.6 125.5h1.3M81 130.6v1.2M81 139.4v1.3M92.5 130.6v1.2M92.5 139.4v1.3M103.9 130.6v1.2"/>
<path d="M103.9 139.4v1.3M116.6 130.6v1.2M116.6 139.4v1.3M150.9 138.2h1.2M150.9 128h1.2M150.9 133.1h1.2M150.9 125.5h1.2M150.9 135.6h1.2M150.9 130.6h1.2M150.9 122.9h1.2M230.9 136.9h8.9M238.5 131.8h1.3"/>
<path d="M255 136.9h1.3M255 131.8h7.6M256.3 124.2h1.3M22.6 148.3h2.5M23.9 153.4h1.2M23.9 158.5h1.2M23.9 143.3h1.2M55.6 153.4h1.3M55.6 156h1.3M55.6 158.5h1.3M55.6 143.3h1.3M55.6 140.7h1.3"/>
<path d="M81 150.9v2.5h35.6v-2.5M92.5 150.9v2.5M103.9 150.9v2.5M150.9 140.7h1.2M158.5 147.1v8.9M161 147.1v3.8M168.7 156h2.5M168.7 147.1h5M233.4 144.5v1.3M22.6 163.6h2.5M22.6 178.8h2.5M23.9 168.7h1.2"/>
<path d="M23.9 173.7h1.2M55.6 168.7h1.3M55.6 173.7h1.3M55.6 171.2h1.3M98.8 161v1.3M22.6 194.1v1.2M23.9 183.9h1.2M55.6 183.9h1.3"/>
</g>
<g fill="#c00">
<circle cx="103.9" cy="153.4" r=".63"/>
<circle cx="92.5" cy="153.4" r=".63"/>
<circle cx="98.8" cy="153.4" r=".63"/>
<circle cx="22.6" cy="148.3" r=".63"/>
<circle cx="22.6" cy="163.6" r=".63"/>
<circle cx="22.6" cy="178.8" r=".63"/>
<circle cx="41.7" cy="34" r=".63"/>
<circle cx="58.2" cy="92.5" r=".63"/>
<circle cx="58.2" cy="105.2" r=".63"/>
<circle cx="121.7" cy="56.9" r=".63"/>
<circle cx="109" cy="51.8" r=".63"/>
<circle cx="107.7" cy="32.8" r=".63"/>
<circle cx="233.4" cy="136.9" r=".63"/>
<circle cx="256.3" cy="131.8" r=".63"/>
<circle cx="101.3" cy="92.5" r=".63"/>
<circle cx="101.3" cy="105.2" r=".63"/>
<circle cx="210.6" cy="31.5" r=".63"/>
<circle cx="223.3" cy="31.5" r=".63"/>
<circle cx="216.9" cy="41.7" r=".63"/>
<circle cx="251.2" cy="18.8" r=".63"/>
<circle cx="251.2" cy="26.4" r=".63"/>
<circle cx="251.2" cy="34" r=".63"/>
<circle cx="251.2" cy="41.7" r=".63"/>
<circle cx="253.7" cy="67.1" r=".63"/>
<circle cx="253.7" cy="74.7" r=".63"/>
<circle cx="283" cy="96.3" r=".63"/>
<circle cx="202.9" cy="23.9" r=".63"/>
<circle cx="201.7" cy="75.9" r=".63"/>
<circle cx="202.9" cy="107.7" r=".63"/>
<circle cx="230.9" cy="107.7" r=".63"/>
<circle cx="216.9" cy="107.7" r=".63"/>
</g>
<use href="#words"/>
</svg>
